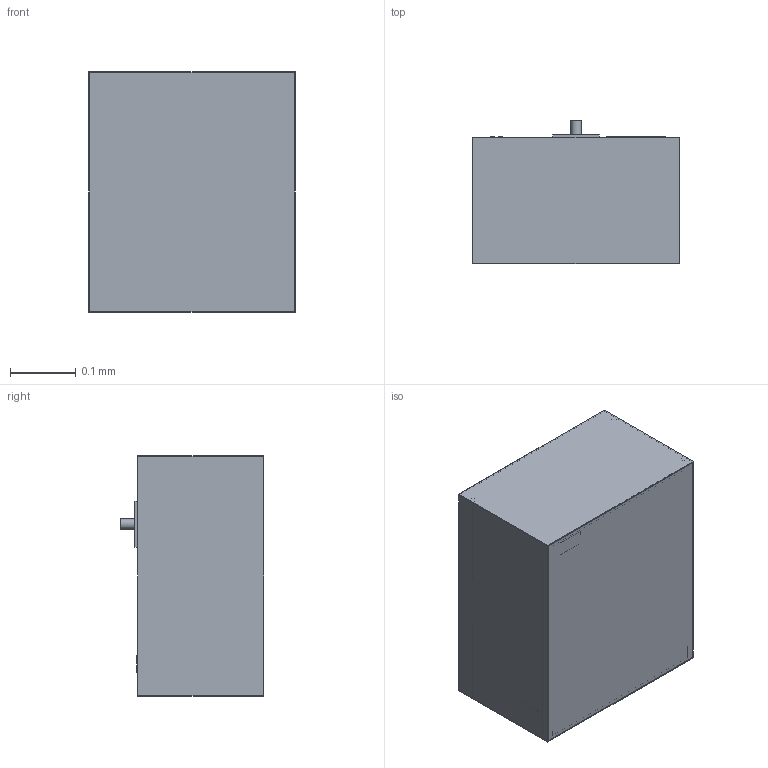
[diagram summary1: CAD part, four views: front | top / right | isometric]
STEP (ISO 10303-21) file: header records copied from the file, then geometry measured from it (millimetres).
FILE_DESCRIPTION(('Open CASCADE Model'),'2;1');
FILE_NAME('Open CASCADE Shape Model','2026-10-04T13:16:32',('Author'),( 'Open CASCADE'),'Open CASCADE STEP processor 7.9','Open CASCADE 7.9' ,'Unknown');
FILE_SCHEMA(('AUTOMOTIVE_DESIGN { 1 0 10303 214 1 1 1 1 }'));
Length unit declared in the file: millimetre
Products named in the file (134): MOD-biofilms; fluid__medium_80_mL; fluid__medium_port; fluid__PBS_60_mL; fluid__PBS_port; fluid__4_paraformaldehyde_40_mL; fluid__4_paraformaldehyde_port; fluid__RNA_preservative_40_mL; fluid__RNA_preservative_port; pump__fluid_manifold; pump__micro_pump_1; pump__valve_1; pump__valve_2; pump__valve_3; pump__valve_4; pump__valve_5; pump__valve_6; pump__valve_7; pump__valve_8; pump__valve_9; pump__valve_10; pump__valve_11; pump__valve_12; pump__valve_13; pump__valve_14; pump__valve_15; pump__valve_16; pump__valve_17; pump__valve_18; pump__valve_19; pump__valve_20; pump__valve_21; pump__valve_22; pump__valve_23; pump__valve_24; pump__manifold_inlet; pump__manifold_outlet; electronics__controller_enclosure_boards_data_storage; electronics__connector_1; electronics__connector_2 ...
Assembly tree (133 placements, depth 2):
  MOD-biofilms
    fluid__medium_80_mL
    fluid__medium_port
    fluid__PBS_60_mL
    fluid__PBS_port
    fluid__4_paraformaldehyde_40_mL
    fluid__4_paraformaldehyde_port
    fluid__RNA_preservative_40_mL
    fluid__RNA_preservative_port
    pump__fluid_manifold
    pump__micro_pump_1
    pump__valve_1
    pump__valve_2
    pump__valve_3
    pump__valve_4
    pump__valve_5
    pump__valve_6
    pump__valve_7
    pump__valve_8
    pump__valve_9
    pump__valve_10
    pump__valve_11
    pump__valve_12
    pump__valve_13
    pump__valve_14
    pump__valve_15
    pump__valve_16
    pump__valve_17
    pump__valve_18
    pump__valve_19
    pump__valve_20
    pump__valve_21
    pump__valve_22
    pump__valve_23
    pump__valve_24
    pump__manifold_inlet
    pump__manifold_outlet
    electronics__controller_enclosure_boards_data_storage
    electronics__connector_1
    electronics__connector_2
    imaging__microscope_base_optics_filter_cubes_camera
    imaging__objective
    imaging__stage_post_1
    imaging__stage_post_2
    imaging__stage_post_3
    imaging__stage_post_4
    imaging__XY_stage_frame_travel_96_5_x_57_9_mm_every_well_over_the_
objective
    imaging__stage_carriage
    imaging__X_stepper
    imaging__Y_stepper
    imaging__illumination_column
    imaging__illumination_arm
    imaging__arm_to_head
    imaging__LED_head_transmitted_light
    sample__cassette_24_wells_SBS_footprint_19_3_mm_pitch
    sample__culture_in_the_wells
    sample__cassette_lid_sealed_and_gas_permeable
    sample__cassette_fluid_port_1
    sample__cassette_fluid_port_2
    sensor__sensor_pack
Bounding box: 0.31 x 0.22 x 0.37 mm (x, y, z)
Volume: 0 mm3; surface area: 1.8 mm2
Topology: 157 solids, 157 shells, 642 faces, 912 edges, 608 vertices
Faces by surface type: plane 478, cylinder 164
Full cylindrical faces by diameter (mm): 0.003 x35, 0.005 x24, 0.006 x4, 0.008 x2, 0.009 x24, 0.01 x4, 0.012 x3, 0.015 x24, 0.016 x25, 0.02 x1, 0.022 x1, 0.028 x1
Entity records: 28998 total; most frequent: DIRECTION 4600, CARTESIAN_POINT 4216, LINE 2080, VECTOR 2080, ORIENTED_EDGE 1824, PCURVE 1824, DEFINITIONAL_REPRESENTATION 1824, AXIS2_PLACEMENT_3D 1104
One B-rep face of a CAD part: STEP entity #20116.
In plain terms, the planar face has unit normal (0, -1, 0).
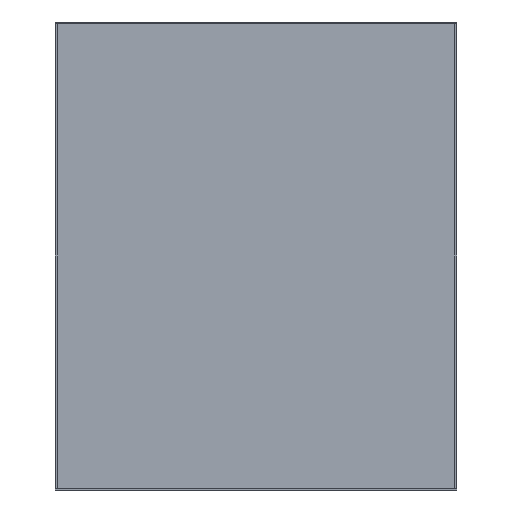
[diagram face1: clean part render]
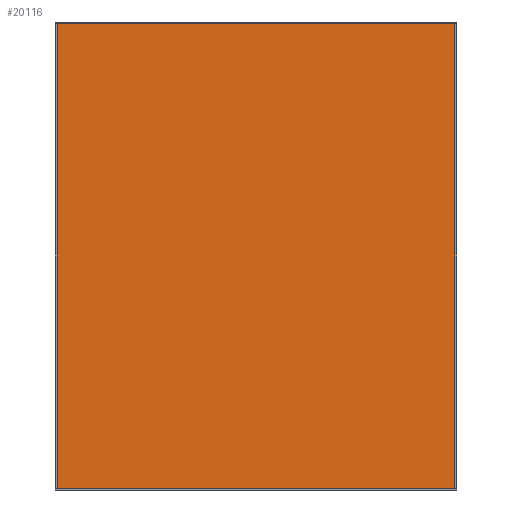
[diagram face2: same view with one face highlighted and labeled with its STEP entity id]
Its self-contained STEP definition (entity closure, numbers rounded to 3 decimals):
#19900 = EDGE_CURVE('',#19901,#19903,#19905,.T.);
#19901 = VERTEX_POINT('',#19902);
#19902 = CARTESIAN_POINT('',(-0.155,-0.096,0.002)
  );
#19903 = VERTEX_POINT('',#19904);
#19904 = CARTESIAN_POINT('',(-0.155,-0.096,
    0.364));
#19905 = SURFACE_CURVE('',#19906,(#19910,#19922),.PCURVE_S1.);
#19906 = LINE('',#19907,#19908);
#19907 = CARTESIAN_POINT('',(-0.155,-0.096,0.002)
  );
#19908 = VECTOR('',#19909,1.);
#19909 = DIRECTION('',(0.,0.,1.));
#19910 = PCURVE('',#19911,#19916);
#19911 = PLANE('',#19912);
#19912 = AXIS2_PLACEMENT_3D('',#19913,#19914,#19915);
#19913 = CARTESIAN_POINT('',(-0.155,-0.096,0.002)
  );
#19914 = DIRECTION('',(1.,0.,0.));
#19915 = DIRECTION('',(0.,0.,1.));
#19916 = DEFINITIONAL_REPRESENTATION('',(#19917),#19921);
#19917 = LINE('',#19918,#19919);
#19918 = CARTESIAN_POINT('',(0.,0.));
#19919 = VECTOR('',#19920,1.);
#19920 = DIRECTION('',(1.,0.));
#19921 = ( GEOMETRIC_REPRESENTATION_CONTEXT(2) 
PARAMETRIC_REPRESENTATION_CONTEXT() REPRESENTATION_CONTEXT('2D SPACE',''
  ) );
#19922 = PCURVE('',#19923,#19928);
#19923 = PLANE('',#19924);
#19924 = AXIS2_PLACEMENT_3D('',#19925,#19926,#19927);
#19925 = CARTESIAN_POINT('',(-0.155,-0.096,0.002)
  );
#19926 = DIRECTION('',(0.,1.,0.));
#19927 = DIRECTION('',(0.,0.,1.));
#19928 = DEFINITIONAL_REPRESENTATION('',(#19929),#19933);
#19929 = LINE('',#19930,#19931);
#19930 = CARTESIAN_POINT('',(0.,0.));
#19931 = VECTOR('',#19932,1.);
#19932 = DIRECTION('',(1.,0.));
#19933 = ( GEOMETRIC_REPRESENTATION_CONTEXT(2) 
PARAMETRIC_REPRESENTATION_CONTEXT() REPRESENTATION_CONTEXT('2D SPACE',''
  ) );
#19951 = PLANE('',#19952);
#19952 = AXIS2_PLACEMENT_3D('',#19953,#19954,#19955);
#19953 = CARTESIAN_POINT('',(-0.155,-0.096,0.002)
  );
#19954 = DIRECTION('',(0.,0.,1.));
#19955 = DIRECTION('',(1.,0.,0.));
#20005 = PLANE('',#20006);
#20006 = AXIS2_PLACEMENT_3D('',#20007,#20008,#20009);
#20007 = CARTESIAN_POINT('',(-0.155,-0.096,
    0.364));
#20008 = DIRECTION('',(0.,0.,1.));
#20009 = DIRECTION('',(1.,0.,0.));
#20020 = EDGE_CURVE('',#20021,#20023,#20025,.T.);
#20021 = VERTEX_POINT('',#20022);
#20022 = CARTESIAN_POINT('',(0.155,-0.096,0.002)
  );
#20023 = VERTEX_POINT('',#20024);
#20024 = CARTESIAN_POINT('',(0.155,-0.096,
    0.364));
#20025 = SURFACE_CURVE('',#20026,(#20030,#20042),.PCURVE_S1.);
#20026 = LINE('',#20027,#20028);
#20027 = CARTESIAN_POINT('',(0.155,-0.096,0.002)
  );
#20028 = VECTOR('',#20029,1.);
#20029 = DIRECTION('',(0.,0.,1.));
#20030 = PCURVE('',#20031,#20036);
#20031 = PLANE('',#20032);
#20032 = AXIS2_PLACEMENT_3D('',#20033,#20034,#20035);
#20033 = CARTESIAN_POINT('',(0.155,-0.096,0.002)
  );
#20034 = DIRECTION('',(1.,0.,0.));
#20035 = DIRECTION('',(0.,0.,1.));
#20036 = DEFINITIONAL_REPRESENTATION('',(#20037),#20041);
#20037 = LINE('',#20038,#20039);
#20038 = CARTESIAN_POINT('',(0.,0.));
#20039 = VECTOR('',#20040,1.);
#20040 = DIRECTION('',(1.,0.));
#20041 = ( GEOMETRIC_REPRESENTATION_CONTEXT(2) 
PARAMETRIC_REPRESENTATION_CONTEXT() REPRESENTATION_CONTEXT('2D SPACE',''
  ) );
#20042 = PCURVE('',#19923,#20043);
#20043 = DEFINITIONAL_REPRESENTATION('',(#20044),#20048);
#20044 = LINE('',#20045,#20046);
#20045 = CARTESIAN_POINT('',(0.,0.31));
#20046 = VECTOR('',#20047,1.);
#20047 = DIRECTION('',(1.,0.));
#20048 = ( GEOMETRIC_REPRESENTATION_CONTEXT(2) 
PARAMETRIC_REPRESENTATION_CONTEXT() REPRESENTATION_CONTEXT('2D SPACE',''
  ) );
#20116 = ADVANCED_FACE('',(#20117),#19923,.F.);
#20117 = FACE_BOUND('',#20118,.F.);
#20118 = EDGE_LOOP('',(#20119,#20140,#20141,#20162));
#20119 = ORIENTED_EDGE('',*,*,#20120,.F.);
#20120 = EDGE_CURVE('',#19901,#20021,#20121,.T.);
#20121 = SURFACE_CURVE('',#20122,(#20126,#20133),.PCURVE_S1.);
#20122 = LINE('',#20123,#20124);
#20123 = CARTESIAN_POINT('',(-0.155,-0.096,0.002)
  );
#20124 = VECTOR('',#20125,1.);
#20125 = DIRECTION('',(1.,0.,0.));
#20126 = PCURVE('',#19923,#20127);
#20127 = DEFINITIONAL_REPRESENTATION('',(#20128),#20132);
#20128 = LINE('',#20129,#20130);
#20129 = CARTESIAN_POINT('',(0.,0.));
#20130 = VECTOR('',#20131,1.);
#20131 = DIRECTION('',(0.,1.));
#20132 = ( GEOMETRIC_REPRESENTATION_CONTEXT(2) 
PARAMETRIC_REPRESENTATION_CONTEXT() REPRESENTATION_CONTEXT('2D SPACE',''
  ) );
#20133 = PCURVE('',#19951,#20134);
#20134 = DEFINITIONAL_REPRESENTATION('',(#20135),#20139);
#20135 = LINE('',#20136,#20137);
#20136 = CARTESIAN_POINT('',(0.,0.));
#20137 = VECTOR('',#20138,1.);
#20138 = DIRECTION('',(1.,0.));
#20139 = ( GEOMETRIC_REPRESENTATION_CONTEXT(2) 
PARAMETRIC_REPRESENTATION_CONTEXT() REPRESENTATION_CONTEXT('2D SPACE',''
  ) );
#20140 = ORIENTED_EDGE('',*,*,#19900,.T.);
#20141 = ORIENTED_EDGE('',*,*,#20142,.T.);
#20142 = EDGE_CURVE('',#19903,#20023,#20143,.T.);
#20143 = SURFACE_CURVE('',#20144,(#20148,#20155),.PCURVE_S1.);
#20144 = LINE('',#20145,#20146);
#20145 = CARTESIAN_POINT('',(-0.155,-0.096,
    0.364));
#20146 = VECTOR('',#20147,1.);
#20147 = DIRECTION('',(1.,0.,0.));
#20148 = PCURVE('',#19923,#20149);
#20149 = DEFINITIONAL_REPRESENTATION('',(#20150),#20154);
#20150 = LINE('',#20151,#20152);
#20151 = CARTESIAN_POINT('',(0.362,0.));
#20152 = VECTOR('',#20153,1.);
#20153 = DIRECTION('',(0.,1.));
#20154 = ( GEOMETRIC_REPRESENTATION_CONTEXT(2) 
PARAMETRIC_REPRESENTATION_CONTEXT() REPRESENTATION_CONTEXT('2D SPACE',''
  ) );
#20155 = PCURVE('',#20005,#20156);
#20156 = DEFINITIONAL_REPRESENTATION('',(#20157),#20161);
#20157 = LINE('',#20158,#20159);
#20158 = CARTESIAN_POINT('',(0.,0.));
#20159 = VECTOR('',#20160,1.);
#20160 = DIRECTION('',(1.,0.));
#20161 = ( GEOMETRIC_REPRESENTATION_CONTEXT(2) 
PARAMETRIC_REPRESENTATION_CONTEXT() REPRESENTATION_CONTEXT('2D SPACE',''
  ) );
#20162 = ORIENTED_EDGE('',*,*,#20020,.F.);
